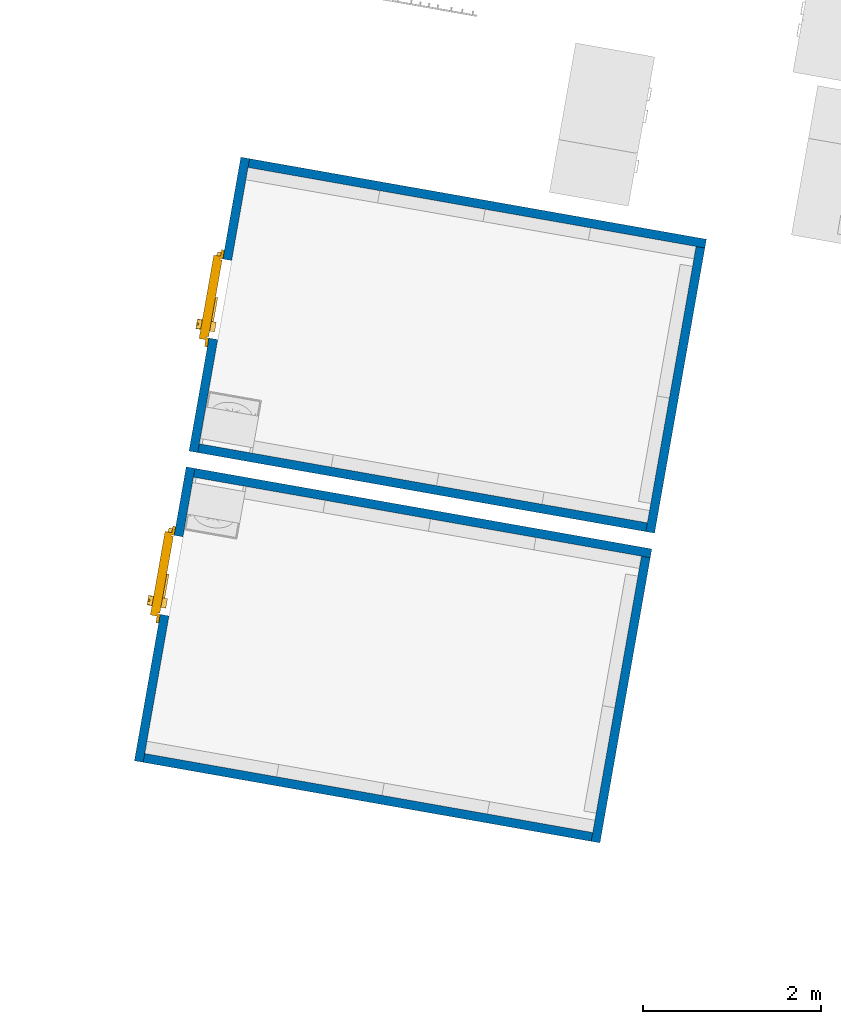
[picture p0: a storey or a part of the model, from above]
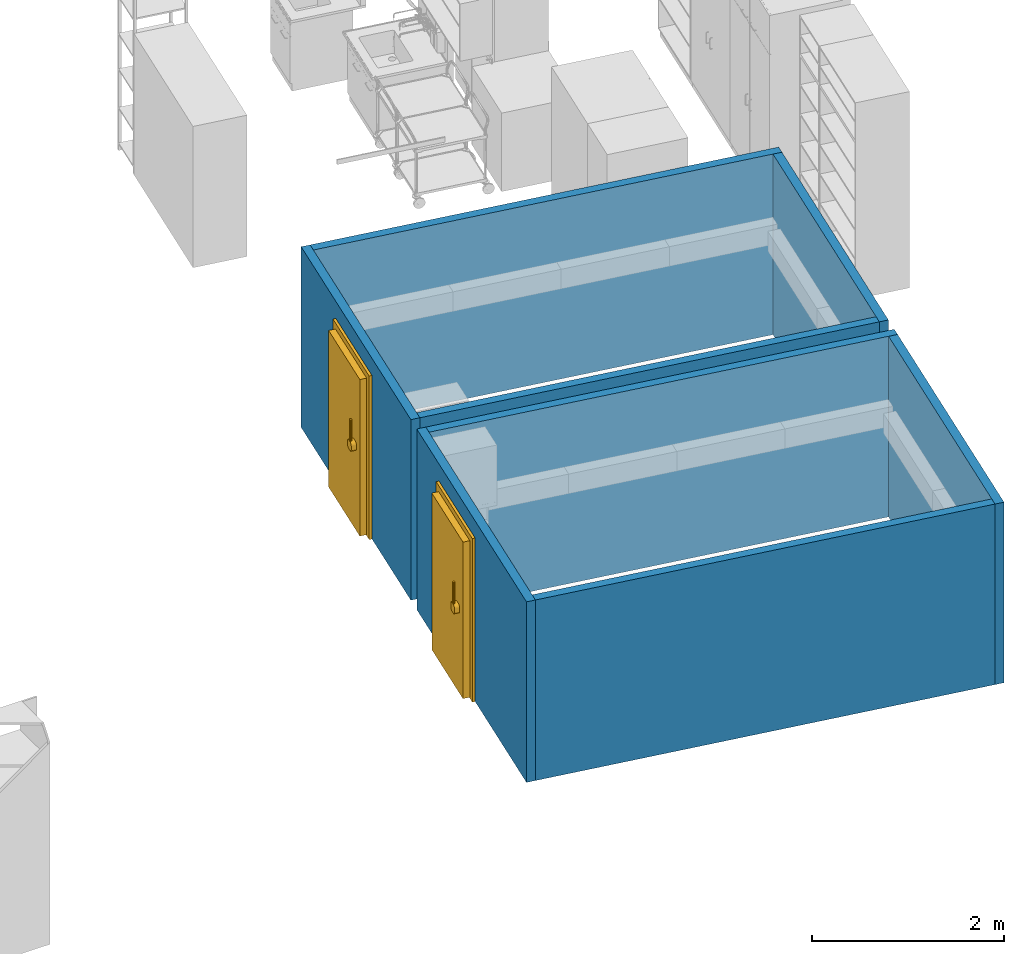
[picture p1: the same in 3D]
Properties of the parts of a building model (IFC2X3)

# File
Description: ViewDefinition [CoordinationView_V2.0]
File name: Projektnummer
Time: 2021-04-22T17:01:40
Written by: The EXPRESS Data Manager Version 5.02.0100.07 : 28 Aug 2013
Made in: 21.1.20.44 - Exporter 21.1.20.44 - Alternativ-UI 21.1.20.44
Comment: STEP Physical File produced by: The EXPRESS Data Manager Version 5.02.0100.07 : 28 Aug 2013 * Module: EDMstepFileFactory/EDMstandAlone * Creation date: Thu Apr 22 17:01:40 2021 * Host: MSB27516-04 * Database: C:\Users\willems\AppData\Local\Temp\c685a05b-38dd-4264-ad8c-4b7700a49285\0224159d-43f5-4bd3-ab2f-e12812f51d72\ifc * Database version: 5507 * Database creation date: Thu Apr 22 17:01:28 2021 * Schema: IFC2X3 * Model: DataRepository.ifc * Model creation date: Thu Apr 22 17:01:28 2021 * Header model: DataRepository.ifc_HeaderModel * Header model creation date: Thu Apr 22 17:01:28 2021 * EDMuser: sdai-user * EDMgroup: sdai-group * License ID and type: 5605 : Permanent license. Expiry date: * EDMstepFileFactory options: 020000

# IfcProject, Projektnummer
LongName: Projektname; Phase: Projektstatus

# IfcSite, Default
RefLatitude: 52, 30, 59, 765625; RefLongitude: 13, 23, 59, 998626; RefElevation: 0 m

# IfcBuilding
Pset_BuildingCommon - NumberOfStoreys: 2

# IfcBuildingStorey: Ebene:Ebene (2)
Name | LongName | Elevation (m)
00 EG | 00 EG | 0 | Pset_AirSideSystemInformation - Name: 00 EG; sets with these values: 2
01 OG | 01 OG | 3 | Pset_ProductRequirements - Name: 01 OG; sets with these values: 2

# IfcBuildingElementProxy: dh_Absaughaube:dh_Absaughaube, dh_Absaughaube:dh_Absaughaube:1414943
In: 01 OG
Type - Material: dh_Edelstahl_Horizontal
Type - Pset_BuildingElementProxyCommon - Reference: dh_Absaughaube
Type - Pset_ManufacturerTypeInformation - Manufacturer: dr.heinekamp
Type - Pset_QuantityTakeOff - Reference: dh_Absaughaube
Pset_BuildingElementProxyCommon - sets with these values: 2

# IfcBuildingElementProxy: dh_Abzug_120+:Abzug 120, dh_Abzug_120+:Abzug 120:1420486
In: 01 OG
Type - Material: dh_Weiß (2), dh_Blau, dh_Bananen gelb
Type - Pset_BuildingElementProxyCommon - Reference: Abzug 120
Type - Pset_ManufacturerTypeInformation - Manufacturer: dr.heinekamp
Type - Pset_QuantityTakeOff - Reference: Abzug 120
Material: dh_Weiß, LED BLAU, LED ROT, LED GRÜN, LED GELB, LED WEISS, dh_Bananen gelb, dh_Glas, Orange, Schwarz, Drehknopf Grün, dh_Schwarz Griff, dh_Steckdose, UHMW, weiß, dh_Lichtgrau, dh_Blau
Pset_BuildingElementProxyCommon - sets with these values: 2

# IfcBuildingElementProxy: dh_Blende:dh_Blende (8)
Type - Material: dh_Weiß
Type - Pset_BuildingElementProxyCommon - Reference: dh_Blende
Type - Pset_ManufacturerTypeInformation - Manufacturer: dr.heinekamp
Type - Pset_QuantityTakeOff - Reference: dh_Blende
Pset_BuildingElementProxyCommon - sets with these values: 2
Name (dh_Blende:dh_Blende:...) | In | Width (m) = Depth (m) | Height (m)
1299124 | 00 EG | 2.74 | 0.02
1351173 | 00 EG | 2.74 | 0.02
1379709 | 01 OG | 0.15 | 0.02
1415218 | 01 OG | 2.74 | 0.02
1420359 | 01 OG
1420617 | 01 OG
1420644 | 01 OG
1443902 | 01 OG | 2.5 | 0.02

# IfcBuildingElementProxy: dh_Doppel_ MEK:DMEK 120 (12)
In: 00 EG
Type - Material: dh_Weiß (2)
Type - Pset_BuildingElementProxyCommon - Reference: DMEK 120
Type - Pset_ManufacturerTypeInformation - Manufacturer: heinekamp
Type - Pset_QuantityTakeOff - Reference: DMEK 120
Material: dh_Weiß
Pset_BuildingElementProxyCommon - sets with these values: 2
Name (dh_Doppel_ MEK:DMEK 120:...)
1308913
1308916
1308919
1308922
1308925
1308928
1308931
1308934
1308937
1308940
1308943
1308946

# IfcBuildingElementProxy: dh_Doppel_ MEK:DMEK 60 (3)
In: 01 OG
Type - Material: dh_EZ blau, dh_Weiß
Type - Pset_BuildingElementProxyCommon - Reference: DMEK 60
Type - Pset_ManufacturerTypeInformation - Manufacturer: heinekamp
Type - Pset_QuantityTakeOff - Reference: DMEK 60
Material: dh_Weiß
Pset_BuildingElementProxyCommon - sets with these values: 2
Name (dh_Doppel_ MEK:DMEK 60:...)
1415066
1415101
1415115

# IfcBuildingElementProxy: dh_Einzel_ Elektrokanal:EK 100, dh_Einzel_ Elektrokanal:EK 100:1354986
In: 00 EG
Type - Material: dh_Weiß
Type - Pset_BuildingElementProxyCommon - Reference: EK 100
Type - Pset_ManufacturerTypeInformation - Manufacturer: heinekamp
Type - Pset_QuantityTakeOff - Reference: EK 100
Pset_BuildingElementProxyCommon - sets with these values: 2
Pset_ProvisionForVoid - Width: 0.155 m; Height: 0.093 m; Depth: 0.155 m

# IfcBuildingElementProxy: dh_Einzel_ Elektrokanal:EK 120 (2)
In: 01 OG
Type - Material: dh_Weiß
Type - Pset_BuildingElementProxyCommon - Reference: EK 120
Type - Pset_ManufacturerTypeInformation - Manufacturer: heinekamp
Type - Pset_QuantityTakeOff - Reference: EK 120
Pset_BuildingElementProxyCommon - sets with these values: 2
Pset_ProvisionForVoid - Width: 0.155 m; Height: 0.093 m; Depth: 0.155 m
Name (dh_Einzel_ Elektrokanal:EK 120:...)
1377853
1378699

# IfcBuildingElementProxy: dh_Einzel_ Elektrokanal:EK 150 (3)
In: 00 EG
Type - Material: dh_Weiß
Type - Pset_BuildingElementProxyCommon - Reference: EK 150
Type - Pset_ManufacturerTypeInformation - Manufacturer: heinekamp
Type - Pset_QuantityTakeOff - Reference: EK 150
Pset_BuildingElementProxyCommon - sets with these values: 2
Name (dh_Einzel_ Elektrokanal:EK 150:...)
1309292 | Pset_ProvisionForVoid - Width: 0.155 m; Height: 0.093 m; Depth: 0.155 m
1309295
1309298

# IfcBuildingElementProxy: dh_Einzel_ Elektrokanal:EK 60 (2)
In: 00 EG
Type - Material: dh_Weiß
Type - Pset_BuildingElementProxyCommon - Reference: EK 60
Type - Pset_ManufacturerTypeInformation - Manufacturer: heinekamp
Type - Pset_QuantityTakeOff - Reference: EK 60
Pset_BuildingElementProxyCommon - sets with these values: 2
Name (dh_Einzel_ Elektrokanal:EK 60:...)
1299237 | Pset_ProvisionForVoid - Width: 0.155 m; Height: 0.093 m; Depth: 0.155 m
1354928

# IfcBuildingElementProxy: dh_Einzel_ Elektrokanal:EK 90 (4)
In: 01 OG
Type - Material: dh_Weiß
Type - Pset_BuildingElementProxyCommon - Reference: EK 90
Type - Pset_ManufacturerTypeInformation - Manufacturer: heinekamp
Type - Pset_QuantityTakeOff - Reference: EK 90
Pset_BuildingElementProxyCommon - sets with these values: 2
Name (dh_Einzel_ Elektrokanal:EK 90:...)
1377922 | Pset_ProvisionForVoid - Width: 0.155 m; Height: 0.093 m; Depth: 0.155 m
1377959
1378706 | Pset_ProvisionForVoid - Width: 0.155 m; Height: 0.093 m; Depth: 0.155 m
1378710

# IfcBuildingElementProxy: dh_Einzel_ MEK:MEK 120 (20)
Type - Material: dh_Weiß, dh_Blau, dh_EZ blau
Type - Pset_BuildingElementProxyCommon - Reference: MEK 120
Type - Pset_ManufacturerTypeInformation - Manufacturer: heinekamp
Type - Pset_QuantityTakeOff - Reference: MEK 120
Material: dh_EZ blau, dh_Weiß
Pset_BuildingElementProxyCommon - sets with these values: 2
Name (dh_Einzel_ MEK:MEK 120:...) | In
1322220 | 00 EG | Pset_ProvisionForVoid - Width: 0.24 m; Height: 0.08 m; Depth: 0.24 m
1322361 | 00 EG
1322491 | 00 EG
1323456 | 00 EG
1323569 | 00 EG
1323669 | 00 EG
1323781 | 00 EG
1325149 | 00 EG
1325230 | 00 EG
1325390 | 00 EG
1325726 | 00 EG
1325863 | 00 EG
1325971 | 00 EG
1326063 | 00 EG
1397288 | 01 OG | Pset_ProvisionForVoid - Width: 0.24 m; Height: 0.08 m; Depth: 0.24 m
1397618 | 01 OG
1415335 | 01 OG
1415393 | 01 OG
1415447 | 01 OG
1420498 | 01 OG

# IfcBuildingElementProxy: dh_Einzel_ MEK:MEK 150 (10)
Type - Material: dh_Weiß, dh_Blau, dh_EZ blau
Type - Pset_BuildingElementProxyCommon - Reference: MEK 150
Type - Pset_ManufacturerTypeInformation - Manufacturer: heinekamp
Type - Pset_QuantityTakeOff - Reference: MEK 150
Material: dh_EZ blau, dh_Weiß
Pset_BuildingElementProxyCommon - sets with these values: 2
Name (dh_Einzel_ MEK:MEK 150:...) | In
1309268 | 00 EG | Pset_ProvisionForVoid - Width: 0.24 m; Height: 0.08 m; Depth: 0.24 m
1322028 | 00 EG
1323095 | 00 EG
1325575 | 00 EG
1326176 | 00 EG
1397393 | 01 OG | Pset_ProvisionForVoid - Width: 0.24 m; Height: 0.08 m; Depth: 0.24 m
1420516 | 01 OG
1424093 | 01 OG
1424187 | 01 OG
1424244 | 01 OG

# IfcBuildingElementProxy: dh_Einzel_ MEK:MEK 60, dh_Einzel_ MEK:MEK 60:1420509
In: 01 OG
Type - Material: dh_Blau, dh_Weiß, dh_EZ blau
Type - Pset_BuildingElementProxyCommon - Reference: MEK 60
Type - Pset_ManufacturerTypeInformation - Manufacturer: heinekamp
Type - Pset_QuantityTakeOff - Reference: MEK 60
Material: dh_EZ blau, dh_Weiß
Pset_BuildingElementProxyCommon - sets with these values: 2
Pset_ProvisionForVoid - Width: 0.24 m; Height: 0.08 m; Depth: 0.24 m

# IfcBuildingElementProxy: dh_Einzel_ MEK:MEK 90, dh_Einzel_ MEK:MEK 90:1415568
In: 01 OG
Type - Material: dh_Weiß, dh_Blau, dh_EZ blau
Type - Pset_BuildingElementProxyCommon - Reference: MEK 90
Type - Pset_ManufacturerTypeInformation - Manufacturer: heinekamp
Type - Pset_QuantityTakeOff - Reference: MEK 90
Material: dh_EZ blau, dh_Weiß
Pset_BuildingElementProxyCommon - sets with these values: 2
Pset_ProvisionForVoid - Width: 0.24 m; Height: 0.08 m; Depth: 0.24 m

# IfcBuildingElementProxy: dh_Einzel_ MEK:MEK 90 (3)
In: 00 EG
Type - Material: dh_Weiß, dh_EZ blau, dh_Blau
Type - Pset_BuildingElementProxyCommon - Reference: MEK 90
Type - Pset_ManufacturerTypeInformation - Manufacturer: heinekamp
Type - Pset_QuantityTakeOff - Reference: MEK 90
Material: dh_EZ blau, dh_Weiß
Pset_BuildingElementProxyCommon - sets with these values: 2
Name (dh_Einzel_ MEK:MEK 90:...)
1309261 | Pset_ProvisionForVoid - Width: 0.24 m; Height: 0.08 m; Depth: 0.24 m
1324014
1324885

# IfcBuildingElementProxy: dh_Energiezelle HWB:HWB 60 tief WHS (2)
In: 00 EG
Type - Material: dh_EZ blau, dh_Weiß, DH Weiß
Type - Pset_BuildingElementProxyCommon - Reference: HWB 60 tief WHS
Type - Pset_ManufacturerTypeInformation - Manufacturer: dr.heinekamp
Type - Pset_QuantityTakeOff - Reference: HWB 60 tief WHS
Material: Gustavsberg Chrome - Polished, Tischplatte, Aluminium 6061, dh_Rot, Gummi, schwarz, UHMW, weiß, DH Weiß, dh_Weiß, dh_Grau, Glas, grün, dh_Griff, Papier, dh_Chrom, dh_Glas WHS, dh_EZ blau
Pset_BuildingElementProxyCommon - sets with these values: 2
Name (dh_Energiezelle HWB:HWB 60 tief WHS:...)
1324252
1324655

# IfcBuildingElementProxy: dh_Energiezelle HWB:HWB 60 tief WHS, dh_Energiezelle HWB:HWB 60 tief WHS:1394126
In: 01 OG
Type - Material: dh_Weiß, DH Weiß, dh_EZ blau
Type - Pset_BuildingElementProxyCommon - Reference: HWB 60 tief WHS
Type - Pset_ManufacturerTypeInformation - Manufacturer: dr.heinekamp
Type - Pset_QuantityTakeOff - Reference: HWB 60 tief WHS
Material: Gustavsberg Chrome - Polished, Tischplatte, Aluminium 6061, dh_Rot, Gummi, schwarz, UHMW, weiß, DH Weiß, dh_Weiß, dh_Grau, Glas, grün, dh_Griff, Papier, dh_Chrom, dh_Glas WHS, dh_EZ blau
Pset_BuildingElementProxyCommon - sets with these values: 2

# IfcBuildingElementProxy: dh_Energiezelle HWB:HWB 60 tief ohne WHS, dh_Energiezelle HWB:HWB 60 tief ohne WHS:1231586
In: 00 EG
Type - Material: DH Weiß, dh_EZ blau, dh_Weiß, dh_Spiegel
Type - Pset_BuildingElementProxyCommon - Reference: HWB 60 tief ohne WHS
Type - Pset_ManufacturerTypeInformation - Manufacturer: dr.heinekamp
Type - Pset_QuantityTakeOff - Reference: HWB 60 tief ohne WHS
Material: dh_Spiegel, Gustavsberg Chrome - Polished, Tischplatte, Aluminium 6061, dh_Rot, Gummi, schwarz, UHMW, weiß, DH Weiß, dh_Weiß, dh_Grau, Glas, grün, dh_Griff, Papier, dh_EZ blau
Pset_BuildingElementProxyCommon - sets with these values: 2

# IfcBuildingElementProxy: dh_Energiezelle ST:EZ_ST120 WHS-T (3)
Type - Material: dh_EZ blau, dh_Weiß (2), dh_Griff
Type - Pset_BuildingElementProxyCommon - Reference: EZ_ST120 WHS-T
Type - Pset_ManufacturerTypeInformation - Manufacturer: dr.heinekamp
Type - Pset_QuantityTakeOff - Reference: EZ_ST120 WHS-T
Material: dh_Griff, dh_Weiß, dh_EZ blau, Stopper
Pset_BuildingElementProxyCommon - sets with these values: 2
Name (dh_Energiezelle ST:EZ_ST120 WHS-T:...) | In
1308734 | 00 EG
1308738 | 00 EG
1404616 | 01 OG

# IfcBuildingElementProxy: dh_Energiezelle ST:EZ_ST120 ohne WHS WHA (2)
In: 01 OG
Type - Material: dh_Weiß, <Unnamed>, dh_EZ blau
Type - Pset_BuildingElementProxyCommon - Reference: EZ_ST120 ohne WHS WHA
Type - Pset_ManufacturerTypeInformation - Manufacturer: dr.heinekamp
Type - Pset_QuantityTakeOff - Reference: EZ_ST120 ohne WHS WHA
Material: dh_EZ blau, Stopper, dh_Weiß
Pset_BuildingElementProxyCommon - sets with these values: 2
Name (dh_Energiezelle ST:EZ_ST120 ohne WHS WHA:...)
1395671
1395717

# IfcBuildingElementProxy: dh_Energiezelle ST:EZ_ST150 WHS-T, dh_Energiezelle ST:EZ_ST150 WHS-T:1378991
In: 01 OG
Type - Material: dh_EZ blau, dh_Weiß (2), dh_Griff
Type - Pset_BuildingElementProxyCommon - Reference: EZ_ST150 WHS-T
Type - Pset_ManufacturerTypeInformation - Manufacturer: dr.heinekamp
Type - Pset_QuantityTakeOff - Reference: EZ_ST150 WHS-T
Material: dh_Griff, dh_Weiß, dh_EZ blau, Stopper
Pset_BuildingElementProxyCommon - sets with these values: 2

# IfcBuildingElementProxy: dh_Energiezelle ST:EZ_ST150 WHS-T, dh_Energiezelle ST:EZ_ST150 WHS-T:1404771
In: 01 OG
Type - Material: dh_Weiß (2), dh_EZ blau, dh_Griff
Type - Pset_BuildingElementProxyCommon - Reference: EZ_ST150 WHS-T
Type - Pset_ManufacturerTypeInformation - Manufacturer: dr.heinekamp
Type - Pset_QuantityTakeOff - Reference: EZ_ST150 WHS-T
Material: dh_Griff, dh_Weiß, dh_EZ blau, Stopper
Pset_BuildingElementProxyCommon - sets with these values: 2

# IfcBuildingElementProxy: dh_Energiezelle ST:EZ_ST90 WHS-T (2)
In: 01 OG
Type - Material: dh_EZ blau, dh_Weiß (2), dh_Griff
Type - Pset_BuildingElementProxyCommon - Reference: EZ_ST90 WHS-T
Type - Pset_ManufacturerTypeInformation - Manufacturer: dr.heinekamp
Type - Pset_QuantityTakeOff - Reference: EZ_ST90 WHS-T
Material: dh_Griff, dh_Weiß, dh_EZ blau, Stopper
Pset_BuildingElementProxyCommon - sets with these values: 2
Name (dh_Energiezelle ST:EZ_ST90 WHS-T:...)
1395029
1395525

# IfcBuildingElementProxy: dh_Energiezelle ST:EZ_ST90 WHS-T (2)
Type - Material: dh_Weiß (2), dh_EZ blau, dh_Griff
Type - Pset_BuildingElementProxyCommon - Reference: EZ_ST90 WHS-T
Type - Pset_ManufacturerTypeInformation - Manufacturer: dr.heinekamp
Type - Pset_QuantityTakeOff - Reference: EZ_ST90 WHS-T
Material: dh_Griff, dh_Weiß, dh_EZ blau, Stopper
Pset_BuildingElementProxyCommon - sets with these values: 2
Name (dh_Energiezelle ST:EZ_ST90 WHS-T:...) | In
1308725 | 00 EG
1404453 | 01 OG

# IfcBuildingElementProxy: dh_Energiezelle ST:EZ_ST90 ohne WHS WHA, dh_Energiezelle ST:EZ_ST90 ohne WHS WHA:1404120
In: 01 OG
Type - Material: dh_EZ blau, <Unnamed>, dh_Weiß
Type - Pset_BuildingElementProxyCommon - Reference: EZ_ST90 ohne WHS WHA
Type - Pset_ManufacturerTypeInformation - Manufacturer: dr.heinekamp
Type - Pset_QuantityTakeOff - Reference: EZ_ST90 ohne WHS WHA
Material: dh_EZ blau, Stopper, dh_Weiß
Pset_BuildingElementProxyCommon - sets with these values: 2

# IfcBuildingElementProxy: dh_Energiezelle-Doppel ST:DEZ_ST120 ohne WHS WHA (4)
In: 01 OG
Type - Material: dh_Glas WHS, dh_EZ blau
Type - Pset_BuildingElementProxyCommon - Reference: DEZ_ST120 ohne WHS WHA
Type - Pset_ManufacturerTypeInformation - Manufacturer: dr.heinekamp
Type - Pset_QuantityTakeOff - Reference: DEZ_ST120 ohne WHS WHA
Material: dh_EZ blau, Stopper, dh_Weiß
Pset_BuildingElementProxyCommon - sets with these values: 2
Name (dh_Energiezelle-Doppel ST:DEZ_ST120 ohne WHS WHA:...)
1418134
1418239
1418294
1418353

# IfcBuildingElementProxy: dh_Energiezelle_Becken:EZ 120 Becken (6)
Type - Material: dh_Grau, Aluminium 6061
Type - Pset_BuildingElementProxyCommon - Reference: EZ 120 Becken
Type - Pset_ManufacturerTypeInformation - Manufacturer: dr.heinekamp
Type - Pset_QuantityTakeOff - Reference: EZ 120 Becken
Material: Aluminium 6061, dh_Rot, Gummi, schwarz, UHMW, weiß, DH Weiß, dh_Armatur Kunststoff, Drehknopf Rot, Drehknopf Grün, Drehknopf Blau, Drehknopf Weiß, Glas, grün, dh_Grau, dh_Lichtgrau, dh_Edelstahl_Horizontal, dh_Papier, dh_Griff, dh_Weiß, EZ_Blau
Pset_BuildingElementProxyCommon - sets with these values: 2
Name (dh_Energiezelle_Becken:EZ 120 Becken:...) | In
1307853 | 00 EG
1308745 | 00 EG
1394683 | 01 OG
1403974 | 01 OG
1415242 | 01 OG
1420386 | 01 OG

# IfcBuildingElementProxy: dh_Energiezelle_Becken:EZ 90 Becken (2)
Type - Material: dh_Grau, dh_Armatur Kunststoff
Type - Pset_BuildingElementProxyCommon - Reference: EZ 90 Becken
Type - Pset_ManufacturerTypeInformation - Manufacturer: dr.heinekamp
Type - Pset_QuantityTakeOff - Reference: EZ 90 Becken
Material: dh_Armatur Kunststoff, Aluminium 6061, dh_Rot, Gummi, schwarz, UHMW, weiß, DH Weiß, Drehknopf Rot, Drehknopf Grün, Drehknopf Blau, Drehknopf Weiß, Glas, grün, dh_Grau, dh_Lichtgrau, dh_Edelstahl_Horizontal, dh_Papier, dh_Griff, dh_Weiß, EZ_Blau
Pset_BuildingElementProxyCommon - sets with these values: 2
Name (dh_Energiezelle_Becken:EZ 90 Becken:...) | In
1356827 | 00 EG
1378726 | 01 OG

# IfcBuildingElementProxy: dh_Energiezelle_Wägetisch:EZW_SI90 WHS-T, dh_Energiezelle_Wägetisch:EZW_SI90 WHS-T:1379196
In: 01 OG
Type - Material: dh_Weiß, dh_EZ blau, dh_Griff
Type - Pset_BuildingElementProxyCommon - Reference: EZW_SI90 WHS-T
Type - Pset_ManufacturerTypeInformation - Manufacturer: dr.heinekamp
Type - Pset_QuantityTakeOff - Reference: EZW_SI90 WHS-T
Material: dh_Griff, dh_Weiß, dh_Tischplatte, dh_Stein Wäge, dh_EZ blau, Stopper
Pset_BuildingElementProxyCommon - sets with these values: 2

# IfcBuildingElementProxy: dh_Gasflaschenschrank:GF120, dh_Gasflaschenschrank:GF120:1372614
In: 01 OG
Type - Material: dh_Weiss, RAL 1004, Gas aa Gasflasche
Type - Pset_BuildingElementProxyCommon - Reference: GF120
Type - Pset_QuantityTakeOff - Reference: GF120
Material: Gas aa Gasflasche, UHMW, weiß, dh_Schwarz Griff, dh_Weiss, dh_Weiß, RAL 1004, dh_Schwarz
Pset_BuildingElementProxyCommon - sets with these values: 2

# IfcBuildingElementProxy: dh_Gerät_Stellfläche Bestand:Laborgerät, dh_Gerät_Stellfläche Bestand:Laborgerät:1436245
In: 01 OG
Type - Material: dh_Stellfläche dh
Type - Pset_BuildingElementProxyCommon - Reference: Laborgerät
Type - Pset_ManufacturerTypeInformation - Manufacturer: dr.heinekamp
Type - Pset_QuantityTakeOff - Reference: Laborgerät
Pset_BuildingElementProxyCommon - sets with these values: 2

# IfcBuildingElementProxy: dh_Gerät_Stellfläche Bestand:Nutzergerät (33)
Type - Material: dh_Stellfläche
Type - Pset_BuildingElementProxyCommon - Reference: Nutzergerät
Type - Pset_ManufacturerTypeInformation - Manufacturer: dr.heinekamp
Type - Pset_QuantityTakeOff - Reference: Nutzergerät
Pset_BuildingElementProxyCommon - sets with these values: 2
Name (dh_Gerät_Stellfläche Bestand:Nutzergerät:...) | In
1354749 | 00 EG
1367644 | 00 EG
1397803 | 01 OG
1398088 | 01 OG
1414965 | 01 OG
1415100 | 01 OG
1415114 | 01 OG
1417491 | 01 OG
1418094 | 01 OG
1418104 | 01 OG
1418116 | 01 OG
1418127 | 01 OG
1421534 | 00 EG
1421750 | 00 EG
1421856 | 00 EG
1421883 | 00 EG
1421902 | 00 EG
1421971 | 00 EG
1423139 | 00 EG
1423339 | 00 EG
1436695 | 01 OG
1443970 | 01 OG
1443989 | 01 OG
1444005 | 01 OG
1444459 | 01 OG
1444487 | 01 OG
1444545 | 01 OG
1444682 | 01 OG
1444733 | 01 OG
1444749 | 01 OG
1444779 | 01 OG
1444811 | 01 OG
1445041 | 01 OG

# IfcBuildingElementProxy: dh_Gerät_Stellfläche Bestand_rund:Nutzergerät (5)
In: 01 OG
Type - Material: Kunststoff, undurchsichtig schwarz, dh_Stellfläche
Type - Pset_BuildingElementProxyCommon - Reference: Nutzergerät
Type - Pset_ManufacturerTypeInformation - Manufacturer: dr.heinekamp
Type - Pset_QuantityTakeOff - Reference: Nutzergerät
Material: dh_Stellfläche
Pset_BuildingElementProxyCommon - sets with these values: 2
Name (dh_Gerät_Stellfläche Bestand_rund:Nutzergerät:...)
1417836
1418095
1418105
1418117
1418128

# IfcBuildingElementProxy: dh_Geräteabluft:dh_Geräteabluft (3)
In: 01 OG
Type - Material: dh_Chrom
Type - Pset_BuildingElementProxyCommon - Reference: dh_Geräteabluft
Type - Pset_ManufacturerTypeInformation - Manufacturer: dr.heinekamp
Type - Pset_QuantityTakeOff - Reference: dh_Geräteabluft
Pset_BuildingElementProxyCommon - sets with these values: 2
Name (dh_Geräteabluft:dh_Geräteabluft:...) | Width (m) = Depth (m)
1414955 | 0.3
1420656 | 0.5
1420808

# IfcBuildingElementProxy: dh_Kittelleiste:K1000 (2)
In: 00 EG
Type - Material: dh_Weiß
Type - Pset_BuildingElementProxyCommon - Reference: K1000
Type - Pset_ManufacturerTypeInformation - Manufacturer: dr.heinekamp
Type - Pset_QuantityTakeOff - Reference: K1000
Pset_BuildingElementProxyCommon - sets with these values: 2
Name (dh_Kittelleiste:K1000:...)
1356747
1357754

# IfcBuildingElementProxy: dh_Kittelleiste:K600, dh_Kittelleiste:K600:1411007
In: 01 OG
Type - Material: dh_Weiß
Type - Pset_BuildingElementProxyCommon - Reference: K600
Type - Pset_ManufacturerTypeInformation - Manufacturer: dr.heinekamp
Type - Pset_QuantityTakeOff - Reference: K600
Pset_BuildingElementProxyCommon - sets with these values: 2

# IfcBuildingElementProxy: dh_Laborhochregal:1000x600x2000, dh_Laborhochregal:1000x600x2000:1351007
In: 00 EG
Type - Material: dh_Grau, dh_Weiss
Type - Pset_BuildingElementProxyCommon - Reference: 1000x600x2000
Type - Pset_ManufacturerTypeInformation - Manufacturer: dr.heinekamp
Type - Pset_QuantityTakeOff - Reference: 1000x600x2000
Material: dh_Weiss, dh_Grau
Pset_BuildingElementProxyCommon - sets with these values: 2

# IfcBuildingElementProxy: dh_Laborhochregal:1000x600x2000, dh_Laborhochregal:1000x600x2000:1338264
In: 00 EG
Type - Material: dh_Weiss, dh_Grau
Type - Pset_BuildingElementProxyCommon - Reference: 1000x600x2000
Type - Pset_ManufacturerTypeInformation - Manufacturer: dr.heinekamp
Type - Pset_QuantityTakeOff - Reference: 1000x600x2000
Pset_BuildingElementProxyCommon - sets with these values: 2

# IfcBuildingElementProxy: dh_Laborhochregal:1200x600x2000, dh_Laborhochregal:1200x600x2000:1299226
In: 00 EG
Type - Material: dh_Weiss, dh_Grau
Type - Pset_BuildingElementProxyCommon - Reference: 1200x600x2000
Type - Pset_ManufacturerTypeInformation - Manufacturer: dr.heinekamp
Type - Pset_QuantityTakeOff - Reference: 1200x600x2000
Pset_BuildingElementProxyCommon - sets with these values: 2

# IfcBuildingElementProxy: dh_Laborhochregal:600x600x2000 (2)
In: 00 EG
Type - Material: dh_Weiss, dh_Grau
Type - Pset_BuildingElementProxyCommon - Reference: 600x600x2000
Type - Pset_ManufacturerTypeInformation - Manufacturer: dr.heinekamp
Type - Pset_QuantityTakeOff - Reference: 600x600x2000
Pset_BuildingElementProxyCommon - sets with these values: 2
Name (dh_Laborhochregal:600x600x2000:...)
1337967
1350997

# IfcBuildingElementProxy: dh_Laborhochregal:900x600x900, dh_Laborhochregal:900x600x900:1298627
In: 00 EG
Type - Material: dh_Weiss, dh_Grau
Type - Pset_BuildingElementProxyCommon - Reference: 900x600x900
Type - Pset_ManufacturerTypeInformation - Manufacturer: dr.heinekamp
Type - Pset_QuantityTakeOff - Reference: 900x600x900
Pset_BuildingElementProxyCommon - sets with these values: 2

# IfcBuildingElementProxy: dh_Laborhochschrank:SL110x600, dh_Laborhochschrank:SL110x600:1350565
In: 00 EG
Type - Material: dh_Griff
Type - Pset_BuildingElementProxyCommon - Reference: SL110x600
Type - Pset_ManufacturerTypeInformation - Manufacturer: dr. heinekamp
Type - Pset_QuantityTakeOff - Reference: SL110x600
Material: dh_Griff, dh_Weiß, dh_Grau
Pset_BuildingElementProxyCommon - sets with these values: 2

# IfcBuildingElementProxy: dh_Laborhochschrank:SL120x600 (3)
Type - Material: dh_Griff
Type - Pset_BuildingElementProxyCommon - Reference: SL120x600
Type - Pset_ManufacturerTypeInformation - Manufacturer: dr. heinekamp
Type - Pset_QuantityTakeOff - Reference: SL120x600
Material: dh_Griff, dh_Weiß, DH Weiß, dh_Grau
Pset_BuildingElementProxyCommon - sets with these values: 2
Name (dh_Laborhochschrank:SL120x600:...) | In
1351017 | 00 EG
1351143 | 00 EG
1394477 | 01 OG

# IfcBuildingElementProxy: dh_Laborhochschrank_1-flg:KSL600x600, dh_Laborhochschrank_1-flg:KSL600x600:1393823
In: 01 OG
Type - Material: dh_Weiß, dh_Griff
Type - Pset_BuildingElementProxyCommon - Reference: KSL600x600
Type - Pset_ManufacturerTypeInformation - Manufacturer: dr. heinekamp
Type - Pset_QuantityTakeOff - Reference: KSL600x600
Material: dh_Griff, dh_Weiß, dh_Grau
Pset_BuildingElementProxyCommon - sets with these values: 2

# IfcBuildingElementProxy: dh_Laborhochschrank_1-flg:SL600x600, dh_Laborhochschrank_1-flg:SL600x600:1350919
In: 00 EG
Type - Material: dh_Weiß, dh_Chrom
Type - Pset_BuildingElementProxyCommon - Reference: SL600x600
Type - Pset_ManufacturerTypeInformation - Manufacturer: dr. heinekamp
Type - Pset_QuantityTakeOff - Reference: SL600x600
Material: dh_Chrom, dh_Griff, dh_Weiß, dh_Grau
Pset_BuildingElementProxyCommon - sets with these values: 2

# IfcBuildingElementProxy: dh_Laborhochschrank_1-flg:SL600x600 (2)
Type - Material: dh_Weiß, dh_Griff
Type - Pset_BuildingElementProxyCommon - Reference: SL600x600
Type - Pset_ManufacturerTypeInformation - Manufacturer: dr. heinekamp
Type - Pset_QuantityTakeOff - Reference: SL600x600
Material: dh_Griff, dh_Weiß, dh_Grau
Pset_BuildingElementProxyCommon - sets with these values: 2
Name (dh_Laborhochschrank_1-flg:SL600x600:...) | In
1350387 | 00 EG
1394226 | 01 OG

# IfcBuildingElementProxy: dh_Medienwand WHA:120 Stehtisch (13)
Type - Material: dh_Glas WHS, dh_Blau, dh_Weiß
Type - Pset_BuildingElementProxyCommon - Reference: 120 Stehtisch
Type - Pset_ManufacturerTypeInformation - Manufacturer: heinekamp
Type - Pset_QuantityTakeOff - Reference: 120 Stehtisch
Material: dh_Weiß, dh_Glas WHS, dh_Blau
Pset_BuildingElementProxyCommon - sets with these values: 2
Name (dh_Medienwand WHA:120 Stehtisch:...) | In
1308772 | 00 EG | Pset_ProvisionForVoid - Width: 0.2 m; Height: 0.08 m; Depth: 0.2 m
1308779 | 00 EG
1395960 | 01 OG
1396066 | 01 OG
1405350 | 01 OG
1418419 | 01 OG
1418470 | 01 OG
1418511 | 01 OG
1418558 | 01 OG
1418617 | 01 OG
1418740 | 01 OG
1418787 | 01 OG
1418854 | 01 OG

# IfcBuildingElementProxy: dh_Medienwand WHA:150 Stehtisch (2)
In: 01 OG
Type - Material: dh_Weiß, dh_Blau, dh_Glas WHS
Type - Pset_BuildingElementProxyCommon - Reference: 150 Stehtisch
Type - Pset_ManufacturerTypeInformation - Manufacturer: heinekamp
Type - Pset_QuantityTakeOff - Reference: 150 Stehtisch
Material: dh_Weiß, dh_Glas WHS, dh_Blau
Pset_BuildingElementProxyCommon - sets with these values: 2
Name (dh_Medienwand WHA:150 Stehtisch:...)
1379288 | Pset_ProvisionForVoid - Width: 0.2 m; Height: 0.08 m; Depth: 0.2 m
1405494

# IfcBuildingElementProxy: dh_Medienwand WHA:90 Sitztisch, dh_Medienwand WHA:90 Sitztisch:1379361
In: 01 OG
Type - Material: dh_Glas WHS, dh_Weiß, dh_Blau
Type - Pset_BuildingElementProxyCommon - Reference: 90 Sitztisch
Type - Pset_ManufacturerTypeInformation - Manufacturer: heinekamp
Type - Pset_QuantityTakeOff - Reference: 90 Sitztisch
Material: dh_Weiß, dh_Glas WHS, dh_Blau
Pset_BuildingElementProxyCommon - sets with these values: 2
Pset_ProvisionForVoid - Width: 0.2 m; Height: 0.08 m; Depth: 0.2 m

# IfcBuildingElementProxy: dh_Medienwand WHA:90 Stehtisch (5)
Type - Material: dh_Weiß, dh_Glas WHS, dh_Blau
Type - Pset_BuildingElementProxyCommon - Reference: 90 Stehtisch
Type - Pset_ManufacturerTypeInformation - Manufacturer: heinekamp
Type - Pset_QuantityTakeOff - Reference: 90 Stehtisch
Pset_BuildingElementProxyCommon - sets with these values: 2
Name (dh_Medienwand WHA:90 Stehtisch:...) | In
1308759 | 00 EG | Pset_ProvisionForVoid - Width: 0.2 m; Height: 0.08 m; Depth: 0.2 m
1395799 | 01 OG
1395852 | 01 OG
1404878 | 01 OG
1405221 | 01 OG

# IfcBuildingElementProxy: dh_Notdusche:dh_Notdusche, dh_Notdusche:dh_Notdusche:1411509
In: 01 OG
Type - Material: Notdusche grün, dh_Schwarz
Type - Pset_BuildingElementProxyCommon - Reference: dh_Notdusche
Type - Pset_ManufacturerTypeInformation - Manufacturer: dr.heinekamp
Type - Pset_QuantityTakeOff - Reference: dh_Notdusche
Material: dh_Schwarz, Notdusche grün
Pset_BuildingElementProxyCommon - sets with these values: 2

# IfcBuildingElementProxy: dh_Notfallschrank 30:NFS3 Regal (4)
Type - Material: dh_Grau, dh_Weiß (2), dh_Griff
Type - Pset_BuildingElementProxyCommon - Reference: NFS3 Regal
Type - Pset_ManufacturerTypeInformation - Manufacturer: dr. heinekamp
Type - Pset_QuantityTakeOff - Reference: NFS3 Regal
Material: UHMW, weiß, dh_Griff, dh_Weiß, Color RGB 045-045-045, Color RAL 3000, Color RGB 145-145-145, Color RGB 212-140-110, Color RGB 187-185-183, dh_Grau
Pset_BuildingElementProxyCommon - sets with these values: 2
Name (dh_Notfallschrank 30:NFS3 Regal:...) | In
1298578 | 00 EG
1415117 | 01 OG
1420334 | 01 OG
1423995 | 01 OG

# IfcBuildingElementProxy: dh_Notfallschrank 30:NFS3 Regal (2)
In: 01 OG
Type - Material: dh_Weiß (2), dh_Griff, dh_Grau
Type - Pset_BuildingElementProxyCommon - Reference: NFS3 Regal
Type - Pset_ManufacturerTypeInformation - Manufacturer: dr. heinekamp
Type - Pset_QuantityTakeOff - Reference: NFS3 Regal
Material: UHMW, weiß, dh_Griff, dh_Weiß, Color RGB 045-045-045, Color RAL 3000, Color RGB 145-145-145, Color RGB 212-140-110, Color RGB 187-185-183, dh_Grau
Pset_BuildingElementProxyCommon - sets with these values: 2
Name (dh_Notfallschrank 30:NFS3 Regal:...)
1373098
1397120

# IfcBuildingElementProxy: dh_Notfallschrank 60_mit Kittelleiste:NFR60, dh_Notfallschrank 60_mit Kittelleiste:NFR60:1307842
In: 00 EG
Type - Material: dh_Weiß (2), dh_Grau, dh_Griff
Type - Pset_BuildingElementProxyCommon - Reference: NFR60
Type - Pset_ManufacturerTypeInformation - Manufacturer: dr. heinekamp
Type - Pset_QuantityTakeOff - Reference: NFR60
Material: UHMW, weiß, dh_Griff, dh_Weiß, dh_Grau
Pset_BuildingElementProxyCommon - sets with these values: 2

# IfcBuildingElementProxy: dh_Servierwagen:50x50 (3)
Type - Classification: E1090300 Food Service Equipment (Uniformat); Material: dh_Edelstahl_Horizontal
Type - Pset_BuildingElementProxyCommon - Reference: 50x50
Type - Pset_ManufacturerTypeInformation - Manufacturer: Eagle Group
Type - Pset_QuantityTakeOff - Reference: 50x50
Type - Pset_ProvisionForVoid - Width: 0.8 m; Depth: 0.6 m
Material: dh_Edelstahl_Horizontal, QF_Finishes_Polished Chrome, QF_Finishes_Aluminum, QF_Finishes_Rubber Black, QF_Finishes_Grey Vinyl, QF_Finishes_Zinc
Pset_BuildingElementProxyCommon - sets with these values: 2
Name (dh_Servierwagen:50x50:...) | In
1367635 | 00 EG
1367638 | 00 EG
1442957 | 01 OG

# IfcBuildingElementProxy: dh_Sicherheitsschrank:GF 90 (2)
In: 00 EG
Type - Material: Aluminium, dh_Schwarz schwach
Type - Pset_BuildingElementProxyCommon - Reference: GF 90
Type - Pset_QuantityTakeOff - Reference: GF 90
Material: dh_Schwarz schwach, dh_Griff, dh_Weiß, UHMW, weiß, dh_Lichtgrau, Aluminium
Pset_BuildingElementProxyCommon - sets with these values: 2
Name (dh_Sicherheitsschrank:GF 90:...)
1299171
1299176

# IfcBuildingElementProxy: dh_Sicherheitswerkbank_Klasse 2:Typ 1400 (2)
In: 01 OG
Type - Material: dh_Deckel, Aluminium 6061, dh_Weiß
Type - Pset_BuildingElementProxyCommon - Reference: Typ 1400
Type - Pset_ManufacturerTypeInformation - Manufacturer: dr.heinekamp
Type - Pset_QuantityTakeOff - Reference: Typ 1400
Material: Aluminium 6061, dh_Schwarz, dh_Weiß, dh_Glas WHS, dh_Armatur Kunststoff, dh_Deckel
Pset_BuildingElementProxyCommon - sets with these values: 2
Name (dh_Sicherheitswerkbank_Klasse 2:Typ 1400:...)
1403617
1420577

# IfcBuildingElementProxy: dh_Spritzschutz:dh_Spritzschutz 90, dh_Spritzschutz:dh_Spritzschutz 90:1308707
In: 00 EG
Type - Material: dh_Glas
Type - Pset_BuildingElementProxyCommon - Reference: dh_Spritzschutz 90
Type - Pset_QuantityTakeOff - Reference: dh_Spritzschutz 90
Pset_BuildingElementProxyCommon - sets with these values: 2
Pset_ProvisionForVoid - Width: 0.005 m; Depth: 0.005 m

# IfcBuildingElementProxy: dh_Stahlregal:Stahlregal-FB6-120 (2)
Type - Material: UHMW, schwarz, Aluminium
Type - Pset_BuildingElementProxyCommon - Reference: Stahlregal-FB6-120
Type - Pset_ManufacturerTypeInformation - Manufacturer: dr.heinekamp
Type - Pset_QuantityTakeOff - Reference: Stahlregal-FB6-120
Material: Aluminium, UHMW, schwarz
Pset_BuildingElementProxyCommon - sets with these values: 2
Pset_ProvisionForVoid - Width: 0.005 m; Height: 0.03 m; Depth: 0.005 m
Name (dh_Stahlregal:Stahlregal-FB6-120:...) | In
1372121 | 00 EG
1420523 | 01 OG

# IfcBuildingElementProxy: dh_Stahlregal:Stahlregal-FB6-150 (4)
In: 00 EG
Type - Material: UHMW, schwarz, Aluminium
Type - Pset_BuildingElementProxyCommon - Reference: Stahlregal-FB6-150
Type - Pset_ManufacturerTypeInformation - Manufacturer: dr.heinekamp
Type - Pset_QuantityTakeOff - Reference: Stahlregal-FB6-150
Material: Aluminium, UHMW, schwarz
Pset_BuildingElementProxyCommon - sets with these values: 2
Name (dh_Stahlregal:Stahlregal-FB6-150:...)
1372299 | Pset_ProvisionForVoid - Width: 0.005 m; Height: 0.03 m; Depth: 0.005 m
1372338
1372353
1372367

# IfcBuildingElementProxy: dh_Stahlregal:Stahlregal-FB6-60, dh_Stahlregal:Stahlregal-FB6-60:1372172
In: 00 EG
Type - Material: UHMW, schwarz, Aluminium
Type - Pset_BuildingElementProxyCommon - Reference: Stahlregal-FB6-60
Type - Pset_ManufacturerTypeInformation - Manufacturer: dr.heinekamp
Type - Pset_QuantityTakeOff - Reference: Stahlregal-FB6-60
Material: Aluminium, UHMW, schwarz
Pset_BuildingElementProxyCommon - sets with these values: 2
Pset_ProvisionForVoid - Width: 0.005 m; Height: 0.03 m; Depth: 0.005 m

# IfcBuildingElementProxy: dh_Stahlregal:Stahlregal-FB6-90 (2)
Type - Material: UHMW, schwarz, Aluminium
Type - Pset_BuildingElementProxyCommon - Reference: Stahlregal-FB6-90
Type - Pset_ManufacturerTypeInformation - Manufacturer: dr.heinekamp
Type - Pset_QuantityTakeOff - Reference: Stahlregal-FB6-90
Material: Aluminium, UHMW, schwarz
Pset_BuildingElementProxyCommon - sets with these values: 2
Pset_ProvisionForVoid - Width: 0.005 m; Height: 0.03 m; Depth: 0.005 m
Name (dh_Stahlregal:Stahlregal-FB6-90:...) | In
1372376 | 00 EG
1415663 | 01 OG

# IfcBuildingElementProxy: dh_Säure-Laugenschrank:GSL 90, dh_Säure-Laugenschrank:GSL 90:1299161
In: 00 EG
Type - Material: dh_Grau, dh_Griff, dh_Weiß (2)
Type - Pset_BuildingElementProxyCommon - Reference: GSL 90
Type - Pset_ManufacturerTypeInformation - Manufacturer: dr. heinekamp
Type - Pset_QuantityTakeOff - Reference: GSL 90
Material: dh_Griff, dh_Weiß, UHMW, weiß, dh_Grau
Pset_BuildingElementProxyCommon - sets with these values: 2

# IfcBuildingElementProxy: dh_Tieftisch:dh_Tieftisch (2)
In: 01 OG
Type - Material: dh_EZ blau, dh_Weiß
Type - Pset_BuildingElementProxyCommon - Reference: dh_Tieftisch
Type - Pset_QuantityTakeOff - Reference: dh_Tieftisch
Material: dh_Weiß, dh_EZ blau
Pset_BuildingElementProxyCommon - sets with these values: 2
Name (dh_Tieftisch:dh_Tieftisch:...)
1378013
1378501

# IfcBuildingElementProxy: dh_Tieftisch:dh_Tieftisch 120, dh_Tieftisch:dh_Tieftisch 120:1378199
In: 01 OG
Type - Material: dh_EZ blau, dh_Weiß
Type - Pset_BuildingElementProxyCommon - Reference: dh_Tieftisch 120
Type - Pset_QuantityTakeOff - Reference: dh_Tieftisch 120
Material: dh_Weiß, dh_EZ blau
Pset_BuildingElementProxyCommon - sets with these values: 2

# IfcBuildingElementProxy: dh_Tisch:dh_Tisch (3)
In: 01 OG
Type - Material: Schwarz, dh_Weiß
Type - Pset_BuildingElementProxyCommon - Reference: dh_Tisch
Type - Pset_ManufacturerTypeInformation - Manufacturer: dr.heinekamp
Type - Pset_QuantityTakeOff - Reference: dh_Tisch
Material: dh_Weiß, dh_EZ blau, Schwarz
Pset_BuildingElementProxyCommon - sets with these values: 2
Name (dh_Tisch:dh_Tisch:...)
1378515
1378623
1378693

# IfcBuildingElementProxy: dh_Tisch_rollbar:Tisch rollbar (6)
In: 00 EG
Type - Material: dh_Tischplatte, dh_EZ blau, dh_Schwarz
Type - Pset_BuildingElementProxyCommon - Reference: Tisch rollbar
Type - Pset_QuantityTakeOff - Reference: Tisch rollbar
Material: dh_Schwarz, dh_EZ blau, dh_Tischplatte
Pset_BuildingElementProxyCommon - sets with these values: 2
Name (dh_Tisch_rollbar:Tisch rollbar:...)
1308952
1309028
1309083
1309084
1309099
1309100

# IfcBuildingElementProxy: dh_Tischplatte Edelstahl:TP Edelstahl, dh_Tischplatte Edelstahl:TP Edelstahl:1308792
In: 00 EG
Type - Material: dh_Edelstahl_Horizontal
Type - Pset_BuildingElementProxyCommon - Reference: TP Edelstahl
Type - Pset_QuantityTakeOff - Reference: TP Edelstahl
Pset_BuildingElementProxyCommon - sets with these values: 2
Pset_ProvisionForVoid - Width: 0.03 m; Height: 0.84 m; Depth: 0.03 m

# IfcBuildingElementProxy: dh_Tischplatte PH:TP PH (5)
In: 01 OG
Type - Material: Phenolharz, Arbeitsplatte mit fester Oberfläche
Type - Pset_BuildingElementProxyCommon - Reference: TP PH
Type - Pset_QuantityTakeOff - Reference: TP PH
Material: Arbeitsplatte mit fester Oberfläche, Phenolharz
Pset_BuildingElementProxyCommon - sets with these values: 2
Name (dh_Tischplatte PH:TP PH:...) | Width (m) = Depth (m) | Height (m)
1379444 | 0.002 | 0.84
1396348 | 0.002 | 0.84
1405894 | 0.002 | 0.84
1418931 | 0.002 | 0.84
1419008

# IfcBuildingElementProxy: dh_Tischplatte Steinzeug Becken varia:dh_Tischplatte Steinzeug Becken varia, dh_Tischplatte Steinzeug Becken varia:dh_Tischplatte Steinzeug Becken varia:1368782
In: 00 EG
Type - Material: dh_Tischplatte
Type - Pset_BuildingElementProxyCommon - Reference: dh_Tischplatte Steinzeug Becken varia
Type - Pset_ManufacturerTypeInformation - Manufacturer: dr.heinekamp
Type - Pset_QuantityTakeOff - Reference: dh_Tischplatte Steinzeug Becken varia
Pset_BuildingElementProxyCommon - sets with these values: 2

# IfcBuildingElementProxy: dh_Tischplatte Steinzeug Becken:dh_Tischplatte Steinzeug Becken (8)
Type - Material: Steinzeug
Type - Pset_BuildingElementProxyCommon - Reference: dh_Tischplatte Steinzeug Becken
Type - Pset_ManufacturerTypeInformation - Manufacturer: dr.heinekamp
Type - Pset_QuantityTakeOff - Reference: dh_Tischplatte Steinzeug Becken
Pset_BuildingElementProxyCommon - sets with these values: 2
Name (dh_Tischplatte Steinzeug Becken:dh_Tischplatte Steinzeug Becken:...) | In
1307861 | 00 EG
1308824 | 00 EG
1356835 | 00 EG
1379615 | 01 OG
1396151 | 01 OG
1405635 | 01 OG
1415314 | 01 OG
1420394 | 01 OG

# IfcBuildingElementProxy: dh_Trichterbecken:Trichterbecken-SI, dh_Trichterbecken:Trichterbecken-SI:1308882
In: 00 EG
Type - Material: dh_Weiß
Type - Pset_BuildingElementProxyCommon - Reference: Trichterbecken-SI
Type - Pset_ManufacturerTypeInformation - Manufacturer: dr.heinekamp
Type - Pset_QuantityTakeOff - Reference: Trichterbecken-SI
Pset_BuildingElementProxyCommon - sets with these values: 2

# IfcBuildingElementProxy: dh_Trichterbecken:Trichterbecken-ST (2)
In: 00 EG
Type - Material: dh_Weiß
Type - Pset_BuildingElementProxyCommon - Reference: Trichterbecken-ST
Type - Pset_ManufacturerTypeInformation - Manufacturer: dr.heinekamp
Type - Pset_QuantityTakeOff - Reference: Trichterbecken-ST
Pset_BuildingElementProxyCommon - sets with these values: 2
Name (dh_Trichterbecken:Trichterbecken-ST:...)
1308873
1308876

# IfcBuildingElementProxy: dh_UB-Becken:UB12-TM (2)
In: 00 EG
Type - Material: dh_Weiß, dh_Griff
Type - Pset_BuildingElementProxyCommon - Reference: UB12-TM
Type - Pset_ManufacturerTypeInformation - Manufacturer: dr.heinekamp
Type - Pset_QuantityTakeOff - Reference: UB12-TM
Material: dh_Griff, dh_Weiß, dh_Grau
Pset_BuildingElementProxyCommon - sets with these values: 2
Name (dh_UB-Becken:UB12-TM:...)
1368933
1368987

# IfcBuildingElementProxy: dh_UB_EIS:dh_UB_EIS, dh_UB_EIS:dh_UB_EIS:1442448
In: 01 OG
Type - Material: dh_Chrom
Type - Pset_BuildingElementProxyCommon - Reference: dh_UB_EIS
Type - Pset_ManufacturerTypeInformation - Manufacturer: dr.heinekamp
Type - Pset_QuantityTakeOff - Reference: dh_UB_EIS
Pset_BuildingElementProxyCommon - sets with these values: 2

# IfcBuildingElementProxy: dh_UB_Spülmaschine:SP 90, dh_UB_Spülmaschine:SP 90:1442720
In: 01 OG
Type - Material: Metal - Steel - Miele - Galvanized, Metal - Stainless Steel - Miele - Satin, Plastic - Miele - Black
Type - Pset_BuildingElementProxyCommon - Reference: SP 90
Type - Pset_QuantityTakeOff - Reference: SP 90
Material: Metal - Stainless Steel - Miele - Satin, Plastic - Miele - Black, Metal - Steel - Miele - Galvanized
Pset_BuildingElementProxyCommon - sets with these values: 2

# IfcBuildingElementProxy: dh_UT60:UT6-Flügeltür, dh_UT60:UT6-Flügeltür:1308901
In: 00 EG
Type - Material: dh_Weiß (3)
Type - Pset_BuildingElementProxyCommon - Reference: UT6-Flügeltür
Type - Pset_ManufacturerTypeInformation - Manufacturer: dr.heinekamp
Type - Pset_QuantityTakeOff - Reference: UT6-Flügeltür
Material: dh_Weiß, dh_Schwarz
Pset_BuildingElementProxyCommon - sets with these values: 2

# IfcBuildingElementProxy: dh_UT60:UT6-Schublade und einer Flügeltür (17)
Type - Material: dh_Weiß (3)
Type - Pset_BuildingElementProxyCommon - Reference: UT6-Schublade und einer Flügeltür
Type - Pset_ManufacturerTypeInformation - Manufacturer: dr.heinekamp
Type - Pset_QuantityTakeOff - Reference: UT6-Schublade und einer Flügeltür
Material: dh_Weiß, dh_Schwarz
Pset_BuildingElementProxyCommon - sets with these values: 2
Name (dh_UT60:UT6-Schublade und einer Flügeltür:...) | In
1308895 | 00 EG
1397018 | 01 OG
1406487 | 01 OG
1406564 | 01 OG
1419354 | 01 OG
1419445 | 01 OG
1419492 | 01 OG
1419605 | 01 OG
1419684 | 01 OG
1419790 | 01 OG
1419871 | 01 OG
1419916 | 01 OG
1419981 | 01 OG
1420044 | 01 OG
1420109 | 01 OG
1420166 | 01 OG
1420205 | 01 OG

# IfcBuildingElementProxy: dh_UT90+:UT9-2 Schubladen nebeneinander und 2 Flügeltüren (2)
In: 01 OG
Type - Material: dh_Weiß (3)
Type - Pset_BuildingElementProxyCommon - Reference: UT9-2 Schubladen nebeneinander und 2 Flügeltüren
Type - Pset_ManufacturerTypeInformation - Manufacturer: heinekamp
Type - Pset_QuantityTakeOff - Reference: UT9-2 Schubladen nebeneinander und 2 Flügeltüren
Material: dh_Weiß, dh_Schwarz
Pset_BuildingElementProxyCommon - sets with these values: 2
Name (dh_UT90+:UT9-2 Schubladen nebeneinander und 2 Flügeltüren:...)
1396564
1396681

# IfcBuildingElementProxy: dh_UT90+:UT9-Schublade und Flügeltüren, dh_UT90+:UT9-Schublade und Flügeltüren:1406404
In: 01 OG
Type - Material: dh_Weiß (3)
Type - Pset_BuildingElementProxyCommon - Reference: UT9-Schublade und Flügeltüren
Type - Pset_ManufacturerTypeInformation - Manufacturer: heinekamp
Type - Pset_QuantityTakeOff - Reference: UT9-Schublade und Flügeltüren
Material: dh_Weiß, dh_Schwarz
Pset_BuildingElementProxyCommon - sets with these values: 2

# IfcBuildingElementProxy: dh_UT90+:UT9-VA (2)
Type - Material: dh_Weiß (3)
Type - Pset_BuildingElementProxyCommon - Reference: UT9-VA
Type - Pset_ManufacturerTypeInformation - Manufacturer: heinekamp
Type - Pset_QuantityTakeOff - Reference: UT9-VA
Material: dh_Weiß, dh_Schwarz
Pset_BuildingElementProxyCommon - sets with these values: 2
Name (dh_UT90+:UT9-VA:...) | In
1308888 | 00 EG
1419251 | 01 OG

# IfcBuildingElementProxy: dh_Wandhängeregal:WHR, dh_Wandhängeregal:WHR:1357867
In: 00 EG
Type - Material: dh_Weiß
Type - Pset_BuildingElementProxyCommon - Reference: WHR
Type - Pset_QuantityTakeOff - Reference: WHR
Pset_BuildingElementProxyCommon - sets with these values: 2

# IfcCovering: Deckensystem:Reinraumdecke 625x625_15 (2)
In: 00 EG
Type - PredefinedType: CEILING
Type - Pset_CoveringCommon - Reference: Reinraumdecke 625x625_15; Material: Mineral tile; TotalThickness: 0.05 m
Type - Pset_ElementShading - Color: Silver
Type - Pset_ManufacturerTypeInformation - Manufacturer: OWA
Type - Pset_QuantityTakeOff - Reference: Reinraumdecke 625x625_15
Classification: C3030210 Suspended Ceilings - Acoustical (Uniformat); Material: OWA_OWAlux 64/4 S3 625x625 0.035 m, OWA_OWAlux 64/4 S3 625x625 0.015 m
Pset_CoveringCommon - Finish: OWA_OWAlux 64/4 S3 625x625;
Name (Deckensystem:Reinraumdecke 625x625_15:...)
1321462
1322017

# IfcDistributionPort (7)
Description: Flow; FlowDirection: SOURCEANDSINK
Name
4 x Port_1420486
Port_1299171
Port_1299176
Port_1372614

# IfcDoor: dh_Tür-Kühlraum:900 x 1981 (2)
In: 00 EG
Type - OperationType: DOUBLE_SWING_RIGHT; ParameterTakesPrecedence: no; Sizeable: no; Material: Finish-EFD-DoorStyle-Stucco_White_Aluminum, Finish-EFD-Casing
Type - dh_Tür-Kühlraum:900 x 1981:1321237 - PanelOperation: DOUBLE_ACTING
Type - Pset_DoorCommon - IsExternal: no; Reference: 900 x 1981
Type - Pset_QuantityTakeOff - Reference: 900 x 1981
OverallHeight: 1.9812 m; OverallWidth: 0.9 m; Material: Finish-EFD-Casing, Finish-EFD-DoorStyle-Stucco_White_Aluminum, Finish-EFD-ComponentMetal, Finish-EFD-LatchBlack, Finish-EFD-LatchGreen, Finish-EFD-Hinge-Bullet
Name (dh_Tür-Kühlraum:900 x 1981:...)
1321237
1321837

# IfcFlowTerminal: dh_-80 TKS:dh_-80 TKS, dh_-80 TKS:dh_-80 TKS:1435998
In: 01 OG
Type - Material: dh_Weiß
Type - Pset_DistributionFlowElementCommon - Reference: dh_-80 TKS
Type - Pset_ManufacturerTypeInformation - Manufacturer: dr.heinekamp
Type - Pset_QuantityTakeOff - Reference: dh_-80 TKS
Material: dh_Weiß, Acetalharz, schwarz
Pset_DistributionFlowElementCommon - sets with these values: 2

# IfcFlowTerminal: dh_Kühlgeräte:KS Labor (2)
In: 01 OG
Type - Material: dh_Weiß, Stahl, verchromt
Type - Pset_DistributionFlowElementCommon - Reference: KS Labor
Type - Pset_QuantityTakeOff - Reference: KS Labor
Material: Stahl, verchromt, dh_Weiß
Pset_DistributionFlowElementCommon - sets with these values: 2
Name (dh_Kühlgeräte:KS Labor:...)
1420551
1424396

# IfcFlowTerminal: dh_Kühlgeräte:KS/TKS Labor (2)
Type - Material: dh_Weiß, Stahl, verchromt
Type - Pset_DistributionFlowElementCommon - Reference: KS/TKS Labor
Type - Pset_QuantityTakeOff - Reference: KS/TKS Labor
Material: Stahl, verchromt, dh_Weiß
Pset_DistributionFlowElementCommon - sets with these values: 2
Name (dh_Kühlgeräte:KS/TKS Labor:...) | In
1307775 | 00 EG
1397697 | 01 OG

# IfcFlowTerminal: dh_Kühlgeräte:TKS Labor, dh_Kühlgeräte:TKS Labor:1424489
In: 01 OG
Type - Material: dh_Weiß, Aluminium 6061
Type - Pset_DistributionFlowElementCommon - Reference: TKS Labor
Type - Pset_QuantityTakeOff - Reference: TKS Labor
Material: Aluminium 6061, dh_Weiß
Pset_DistributionFlowElementCommon - sets with these values: 2

# IfcFurnishingElement: dh_Einfügepunkt:dh_Einfügepunkt, dh_Einfügepunkt:dh_Einfügepunkt:1445079
In: 00 EG
Type - Material: Drehknopf Blau
Type - Pset_ManufacturerTypeInformation - Manufacturer: dr.heinekamp
Type - Pset_QuantityTakeOff - Reference: dh_Einfügepunkt

# IfcWallStandardCase: Basiswand:GK 10.0 (8)
In: 00 EG
Type - PredefinedType: STANDARD; Material: Gipswandbauplatte 0.0125 m, Wärmedämmung - hart 0.075 m, Gipswandbauplatte 0.0125 m
Type - Pset_QuantityTakeOff - Reference: GK 10.0
Type - Pset_ReinforcementBarPitchOfWall - Reference: GK 10.0
Type - Pset_WallCommon - Reference: GK 10.0; ThermalTransmittance: 0.458438 kg/K/s3; IsExternal: no
Pset_QuantityTakeOff - sets with these values: 2
Pset_WallCommon - ExtendToStructure: no; LoadBearing: no
Name (Basiswand:GK 10.0:...)
1316931
1320644
1320766
1320834
1321833
1321834
1321835
1321836
